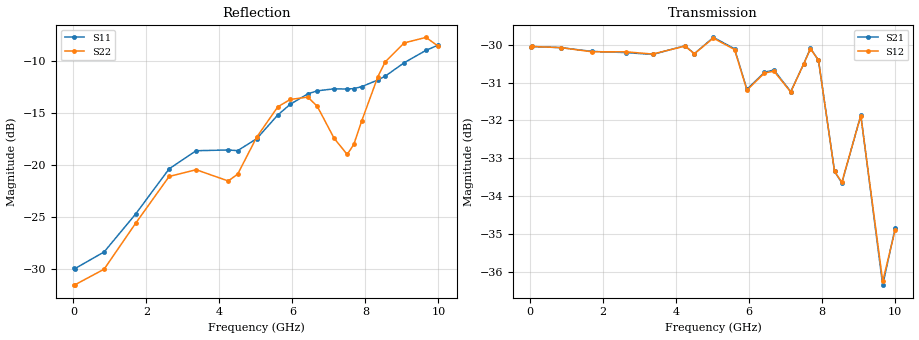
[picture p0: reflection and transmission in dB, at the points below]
! Integrated Device Technology
! Corporate Headquarters
! 6024 Silver Creek Valley Road
! San Jose, CA 95138  USA
! Phone:  1-408-284-8200
! Toll Free:  1-800-223-1366
! Webpage:  http://www.idt.com/
! Timing and RF Division
! 515 Groton Road, Suite 102
! Westford, MA 01886-6024
! Device:  F1958
! Description: 7-bit 0.25 dB Digital Step Attenuator
! Frequency:  0.001 -  6.000 GHz
! Package:  4x4 mm Thin QFN Plastic Package: 24 pin
! Ports:  2 RF, 12 DC
!  Pin  1  = D0
!  Pin  2  = VDD
!  Pin  3  = VMODE
!  Pin  4  = GND
!  Pin  5  = RF1  =  Port 1
!  Pin  6  = GND
!  Pin  7  = GND
!  Pin  8  = GND
!  Pin  9  = GND
!  Pin 10  = GND
!  Pin 11  = GND
!  Pin 12  = GND
!  Pin 13  = GND
!  Pin 14  = RF2  =  Port 2
!  Pin 15  = GND
!  Pin 16  = LE
!  Pin 17  = CLK
!  Pin 18  = DATA
!  Pin 19  = D6
!  Pin 20  = D5
!  Pin 21  = D4
!  Pin 22  = D3
!  Pin 23  = D2
!  Pin 24  = D1
! State:  117
! Atten State:  29.25 dB
! Voltage:  +3.30 Volts
! Current:  0.257 mA
! Data:  The device was measured on a F1958 evaluation board which has
!  individual transmission lines to the RF pins.  Data was collected
!  using a calibrated network analyzer.  The evaluation board was
!  de-embedded using Automatic Fixture Removal (AFR).
!  The reference plane is the edge of the package pin.
! Misc:
!  Action Tracker AT0419
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# GHz S dB R 50
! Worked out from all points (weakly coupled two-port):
!   500 points, 20 MHz to 10 GHz, reference 50 ohm
!   highest |S21| = -29.81 dB at 5.02 GHz (marker M1); lowest = -36.3 dB at 9.66 GHz (marker M2)
!   lowest |S11| = -29.9 dB at 40 MHz (marker M3), VSWR 1.07, Z = 46.9 - j0.0421 ohm
!   |S11| at or under -10 dB: start of sweep to 9.148 GHz
!   |S22| runs from -31.7 to -7.5 dB; largest |S21 - S12| = 0.00029
!   S11 on the Smith chart (normalised r, x): 20 MHz: 0.94, -0.00; 6.42 GHz: 0.67, +0.17; 10 GHz: 0.68, +0.58
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0.02  -29.89 -178.9  -30.06 -0.2  -30.06 -0.1  -31.50 -179.0
0.04  -29.92 -179.2  -30.05 -0.4  -30.05 -0.4  -31.47 -178.6
0.84  -28.32 170.7  -30.08 -9.6  -30.08 -9.6  -29.97 171.9
1.7  -24.70 170.5  -30.18 -19.2  -30.19 -19.1  -25.59 170.6
2.62  -20.36 176.5  -30.21 -29.4  -30.19 -29.5  -21.09 179.7
3.36  -18.62 -176.1  -30.26 -38.3  -30.25 -38.5  -20.44 -170.2
4.24  -18.55 -179.4  -30.03 -48.2  -30.04 -48.2  -21.52 168.0
4.5  -18.61 174.7  -30.24 -51.9  -30.24 -52.0  -20.86 150.6
5.02  -17.47 160.4  -29.81 -58.5  -29.83 -58.5  -17.32 137.8
5.6  -15.19 150.5  -30.11 -67.2  -30.13 -67.3  -14.41 139.8
5.94  -14.17 148.1  -31.18 -71.3  -31.20 -71.2  -13.71 148.3
6.42  -13.17 147.4  -30.73 -76.7  -30.75 -76.8  -13.48 156.8
6.68  -12.88 146.5  -30.67 -79.5  -30.70 -79.3  -14.37 157.3
7.14  -12.69 142.7  -31.24 -85.3  -31.25 -85.2  -17.42 151.4
7.5  -12.71 138.2  -30.50 -88.8  -30.50 -88.7  -18.98 119.4
7.68  -12.67 135.3  -30.10 -94.3  -30.11 -94.3  -18.02 99.2
7.9  -12.48 128.9  -30.41 -103.8  -30.41 -103.9  -15.74 89.1
8.34  -11.84 118.8  -33.34 -110.8  -33.34 -111.0  -11.53 84.0
8.54  -11.48 115.8  -33.65 -102.9  -33.63 -103.0  -10.11 86.3
9.06  -10.19 106.7  -31.86 -113.7  -31.87 -113.7  -8.29 97.6
9.66  -9.00 100.7  -36.34 -109.7  -36.24 -109.4  -7.76 110.3
10  -8.49 99.8  -34.84 -95.1  -34.89 -95.0  -8.63 114.0
